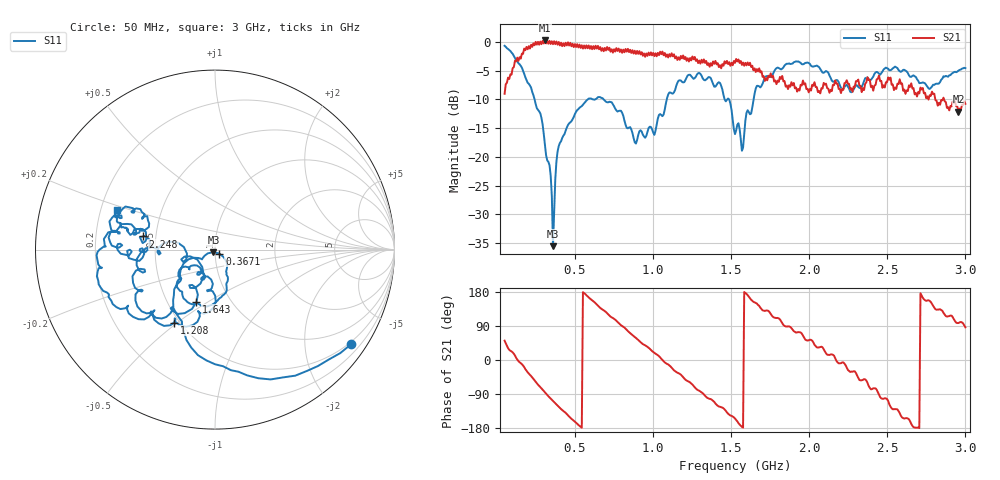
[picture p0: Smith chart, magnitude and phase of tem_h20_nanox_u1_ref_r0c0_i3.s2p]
! nanovna_capture.py 2026-10-26T21:52:13+0900
! NanoVNA-F_V2 fw 0.6.0 SN 4A3639384505514B
! cal: load open short thru cal'ed  over 50000000-3000000000 Hz, 201 points
! points 401, avg 4
! TEM h=20, genuine Nano X, 0 deg, centred, interleaved run G3
# HZ S RI R 50
! S12 and S22 are not measured (written as 0)
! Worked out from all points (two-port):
!   401 points, 50 MHz to 3 GHz, reference 50 ohm
!   highest |S21| = 0.24 dB at 308.1 MHz (marker M1); lowest = -12.2 dB at 2.956 GHz (marker M2)
!   |S21| within 3 dB of the highest: 130.9931 MHz to 131.2786 MHz (285.5 kHz wide, 0.218 % of centre); 154.6 MHz to 1.14 GHz (985.7 MHz wide, 152 % of centre) (the widest 2 of 10)
!   lowest |S11| = -35.5 dB at 359.8 MHz (marker M3), VSWR 1.03, Z = 49.1 - j1.4 ohm
!   |S11| at or under -10 dB: 241.9 MHz to 583.2 MHz (341.3 MHz wide, 82.7 % of centre); 683.3 MHz to 1.088 GHz (405 MHz wide, 45.7 % of centre); 1.487 GHz to 1.644 GHz (157.3 MHz wide, 10 % of centre) (the widest 3 of 5)
!   S12 and S22 are empty: the file has one direction only
!   S11 on the Smith chart (normalised r, x): 50 MHz: 0.44, -3.14; 367.1 MHz: 1.05, -0.05; 1.208 GHz: 0.47, -0.49; 1.643 GHz: 0.69, -0.45; 2.248 GHz: 0.42, +0.07; 3 GHz: 0.27, +0.18
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5e7  0.7587 -0.5269  0.2223 0.2744  0 0  0 0
1.75375e8  -0.1593 -0.5032  0.8268 -0.2826  0 0  0 0
3.08125e8  -0.1188 -0.0455  0.0822 -1.025  0 0  0 0
3.5975e8  -0.00882 -0.0142  -0.2956 -0.9072  0 0  0 0
3.67125e8  0.0244 -0.0218  -0.3657 -0.9447  0 0  0 0
4.04e8  0.0629 -0.1163  -0.5576 -0.7452  0 0  0 0
5.44125e8  0.0207 -0.2757  -0.9343 -0.0208  0 0  0 0
7.80125e8  -0.1908 -0.1624  -0.1096 0.8669  0 0  0 0
8.9075e8  -0.083 -0.1007  0.4125 0.6685  0 0  0 0
1.03825e9  -0.03 -0.2293  0.754 0.1338  0 0  0 0
1.207875e9  -0.2282 -0.4066  0.4544 -0.5815  0 0  0 0
1.429125e9  -0.4359 -0.0526  -0.3452 -0.5226  0 0  0 0
1.525e9  -0.1559 -0.0226  -0.5913 -0.2841  0 0  0 0
1.576625e9  -0.0712 -0.0968  -0.6604 -0.019  0 0  0 0
1.643e9  -0.1035 -0.2921  -0.5057 0.2527  0 0  0 0
1.783125e9  -0.4258 -0.3878  -0.1661 0.4298  0 0  0 0
2.019125e9  -0.6103 0.0191  0.2653 0.3298  0 0  0 0
2.24775e9  -0.4006 0.0734  0.388 -0.191  0 0  0 0
2.51325e9  -0.5557 0.1048  -0.2142 -0.4174  0 0  0 0
2.712375e9  -0.3929 0.1948  -0.3996 0.0262  0 0  0 0
2.95575e9  -0.5418 0.1515  -0.0328 0.2444  0 0  0 0
3e9  -0.5466 0.2228  0.0187 0.2883  0 0  0 0
